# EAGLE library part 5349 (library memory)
MEMORY

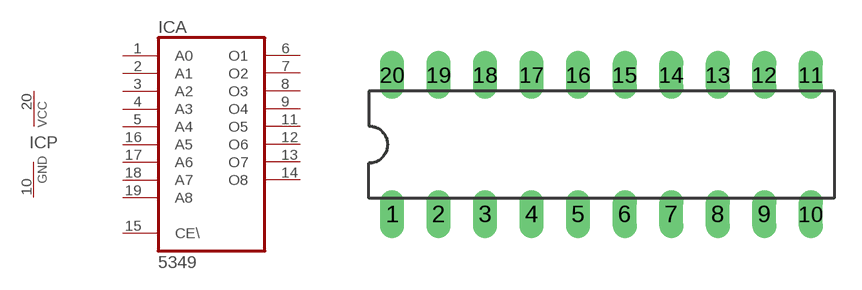
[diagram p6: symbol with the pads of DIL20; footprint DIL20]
Designator prefix IC; gates A=5349 P=PWRN

## 5349  [DIL20]
1  A:A0  in
2  A:A1  in
3  A:A2  in
4  A:A3  in
5  A:A4  in
6  A:O1  hiz
7  A:O2  hiz
8  A:O3  hiz
9  A:O4  hiz
10  P:GND  pwr
11  A:O5  hiz
12  A:O6  hiz
13  A:O7  hiz
14  A:O8  hiz
15  A:CE\  in
16  A:A5  in
17  A:A6  in
18  A:A7  in
19  A:A8  in
20  P:VCC  pwr

## Footprint DIL20 (pad centres in mm)
Dual In Line Package
drill 0.813 long: 1 -11.43,-3.81; 2 -8.89,-3.81; 3 -6.35,-3.81; 4 -3.81,-3.81; 5 -1.27,-3.81; 6 1.27,-3.81; 7 3.81,-3.81; 8 6.35,-3.81; 9 8.89,-3.81; 10 11.43,-3.81; 11 11.43,3.81; 12 8.89,3.81; 13 6.35,3.81; 14 3.81,3.81; 15 1.27,3.81; 16 -1.27,3.81; 17 -3.81,3.81; 18 -6.35,3.81; 19 -8.89,3.81; 20 -11.43,3.81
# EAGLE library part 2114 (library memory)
MEMORY

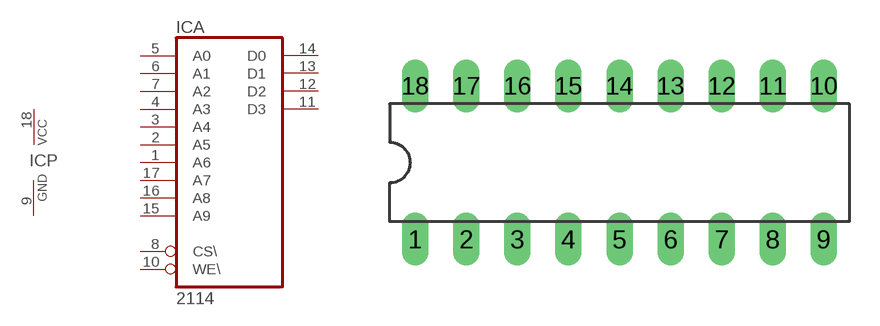
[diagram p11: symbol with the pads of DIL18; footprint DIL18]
Designator prefix IC; gates A=2114 P=PWRN

## 2114  [DIL18]
1  A:A6  in
2  A:A5  in
3  A:A4  in
4  A:A3  in
5  A:A0  in
6  A:A1  in
7  A:A2  in
8  A:CS\  in
9  P:GND  pwr
10  A:WE\  in
11  A:D3
12  A:D2
13  A:D1
14  A:D0
15  A:A9  in
16  A:A8  in
17  A:A7  in
18  P:VCC  pwr

## Footprint DIL18 (pad centres in mm)
Dual In Line Package
drill 0.813 long: 1 -10.16,-3.81; 2 -7.62,-3.81; 3 -5.08,-3.81; 4 -2.54,-3.81; 5 0,-3.81; 6 2.54,-3.81; 7 5.08,-3.81; 8 7.62,-3.81; 9 10.16,-3.81; 10 10.16,3.81; 11 7.62,3.81; 12 5.08,3.81; 13 2.54,3.81; 14 0,3.81; 15 -2.54,3.81; 16 -5.08,3.81; 17 -7.62,3.81; 18 -10.16,3.81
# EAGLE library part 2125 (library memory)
MEMORY

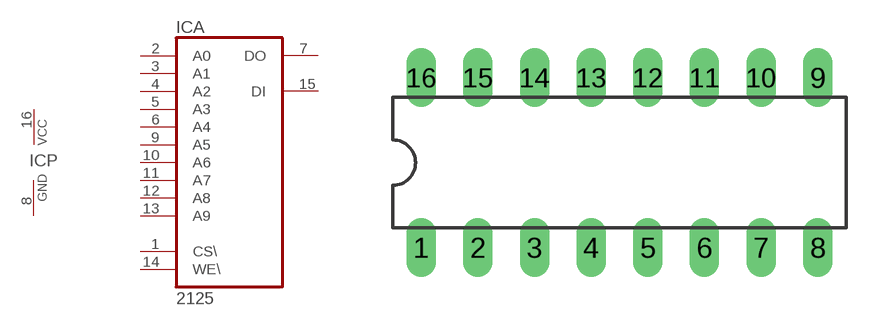
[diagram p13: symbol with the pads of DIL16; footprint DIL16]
Designator prefix IC; gates A=2125 P=PWRN

## 2125  [DIL16]
1  A:CS\  in
2  A:A0  in
3  A:A1  in
4  A:A2  in
5  A:A3  in
6  A:A4  in
7  A:DO  hiz
8  P:GND  pwr
9  A:A5  in
10  A:A6  in
11  A:A7  in
12  A:A8  in
13  A:A9  in
14  A:WE\  in
15  A:DI  in
16  P:VCC  pwr

## Footprint DIL16 (pad centres in mm)
Dual In Line Package
drill 0.813 long: 1 -8.89,-3.81; 2 -6.35,-3.81; 3 -3.81,-3.81; 4 -1.27,-3.81; 5 1.27,-3.81; 6 3.81,-3.81; 7 6.35,-3.81; 8 8.89,-3.81; 9 8.89,3.81; 10 6.35,3.81; 11 3.81,3.81; 12 1.27,3.81; 13 -1.27,3.81; 14 -3.81,3.81; 15 -6.35,3.81; 16 -8.89,3.81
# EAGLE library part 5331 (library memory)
MEMORY

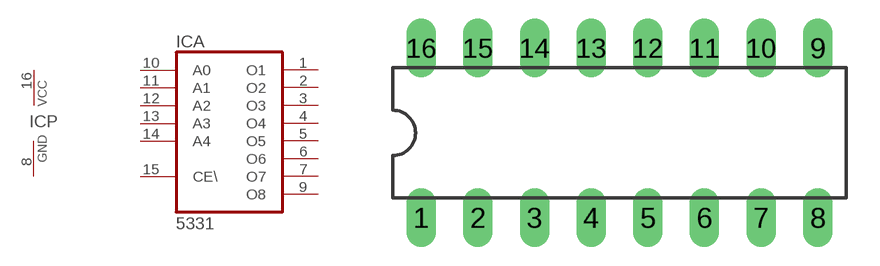
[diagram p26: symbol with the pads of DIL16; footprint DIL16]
Designator prefix IC; gates A=5331 P=PWRN

## 5331  [DIL16]
1  A:O1  hiz
2  A:O2  hiz
3  A:O3  hiz
4  A:O4  hiz
5  A:O5  hiz
6  A:O6  hiz
7  A:O7  hiz
8  P:GND  pwr
9  A:O8  hiz
10  A:A0  in
11  A:A1  in
12  A:A2  in
13  A:A3  in
14  A:A4  in
15  A:CE\  in
16  P:VCC  pwr

## Footprint DIL16 (pad centres in mm)
Dual In Line Package
drill 0.813 long: 1 -8.89,-3.81; 2 -6.35,-3.81; 3 -3.81,-3.81; 4 -1.27,-3.81; 5 1.27,-3.81; 6 3.81,-3.81; 7 6.35,-3.81; 8 8.89,-3.81; 9 8.89,3.81; 10 6.35,3.81; 11 3.81,3.81; 12 1.27,3.81; 13 -1.27,3.81; 14 -3.81,3.81; 15 -6.35,3.81; 16 -8.89,3.81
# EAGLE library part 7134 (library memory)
MEMORY

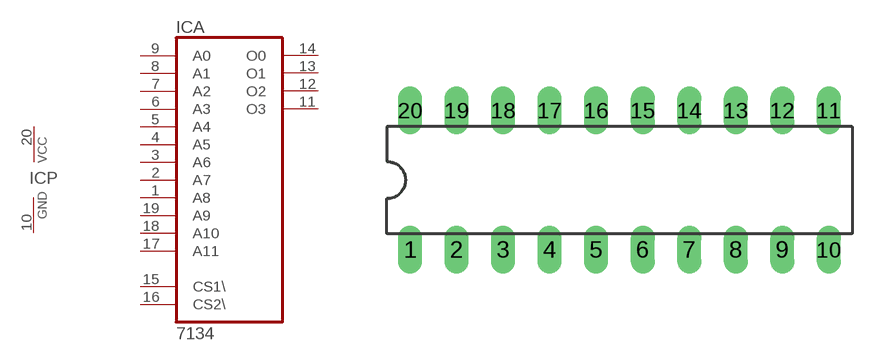
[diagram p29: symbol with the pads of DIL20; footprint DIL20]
Designator prefix IC; gates A=7134 P=PWRN

## 7134  [DIL20]
1  A:A8  in
2  A:A7  in
3  A:A6  in
4  A:A5  in
5  A:A4  in
6  A:A3  in
7  A:A2  in
8  A:A1  in
9  A:A0  in
10  P:GND  pwr
11  A:O3  hiz
12  A:O2  hiz
13  A:O1  hiz
14  A:O0  hiz
15  A:CS1\  in
16  A:CS2\  in
17  A:A11  in
18  A:A10  in
19  A:A9  in
20  P:VCC  pwr

## Footprint DIL20 (pad centres in mm)
Dual In Line Package
drill 0.813 long: 1 -11.43,-3.81; 2 -8.89,-3.81; 3 -6.35,-3.81; 4 -3.81,-3.81; 5 -1.27,-3.81; 6 1.27,-3.81; 7 3.81,-3.81; 8 6.35,-3.81; 9 8.89,-3.81; 10 11.43,-3.81; 11 11.43,3.81; 12 8.89,3.81; 13 6.35,3.81; 14 3.81,3.81; 15 1.27,3.81; 16 -1.27,3.81; 17 -3.81,3.81; 18 -6.35,3.81; 19 -8.89,3.81; 20 -11.43,3.81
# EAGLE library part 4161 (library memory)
MEMORY

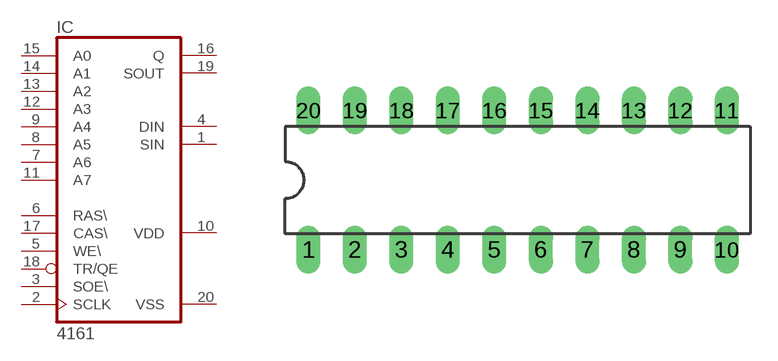
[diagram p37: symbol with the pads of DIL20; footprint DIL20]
Designator prefix IC

## 4161  [DIL20]
1  SIN  in
2  SCLK  in
3  SOE\  in
4  DIN  in
5  WE\  in
6  RAS\  in
7  A6  in
8  A5  in
9  A4  in
10  VDD  pwr
11  A7  in
12  A3  in
13  A2  in
14  A1  in
15  A0  in
16  Q  hiz
17  CAS\  in
18  TR/QE  in
19  SOUT  out
20  VSS  pwr

## Footprint DIL20 (pad centres in mm)
Dual In Line Package
drill 0.813 long: 1 -11.43,-3.81; 2 -8.89,-3.81; 3 -6.35,-3.81; 4 -3.81,-3.81; 5 -1.27,-3.81; 6 1.27,-3.81; 7 3.81,-3.81; 8 6.35,-3.81; 9 8.89,-3.81; 10 11.43,-3.81; 11 11.43,3.81; 12 8.89,3.81; 13 6.35,3.81; 14 3.81,3.81; 15 1.27,3.81; 16 -1.27,3.81; 17 -3.81,3.81; 18 -6.35,3.81; 19 -8.89,3.81; 20 -11.43,3.81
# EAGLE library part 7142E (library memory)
MEMORY

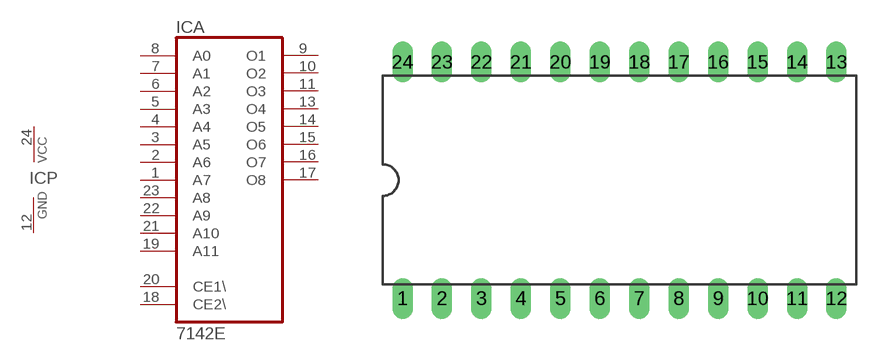
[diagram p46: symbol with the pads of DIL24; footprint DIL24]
Designator prefix IC; gates A=7142E P=PWRN

## 7142E  [DIL24]
1  A:A7  in
2  A:A6  in
3  A:A5  in
4  A:A4  in
5  A:A3  in
6  A:A2  in
7  A:A1  in
8  A:A0  in
9  A:O1  hiz
10  A:O2  hiz
11  A:O3  hiz
12  P:GND  pwr
13  A:O4  hiz
14  A:O5  hiz
15  A:O6  hiz
16  A:O7  hiz
17  A:O8  hiz
18  A:CE2\  in
19  A:A11  in
20  A:CE1\  in
21  A:A10  in
22  A:A9  in
23  A:A8  in
24  P:VCC  pwr

## Footprint DIL24 (pad centres in mm)
Dual In Line Package
drill 0.813 long: 1 -13.97,-7.62; 2 -11.43,-7.62; 3 -8.89,-7.62; 4 -6.35,-7.62; 5 -3.81,-7.62; 6 -1.27,-7.62; 7 1.27,-7.62; 8 3.81,-7.62; 9 6.35,-7.62; 10 8.89,-7.62; 11 11.43,-7.62; 12 13.97,-7.62; 13 13.97,7.62; 14 11.43,7.62; 15 8.89,7.62; 16 6.35,7.62; 17 3.81,7.62; 18 1.27,7.62; 19 -1.27,7.62; 20 -3.81,7.62; 21 -6.35,7.62; 22 -8.89,7.62; 23 -11.43,7.62; 24 -13.97,7.62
